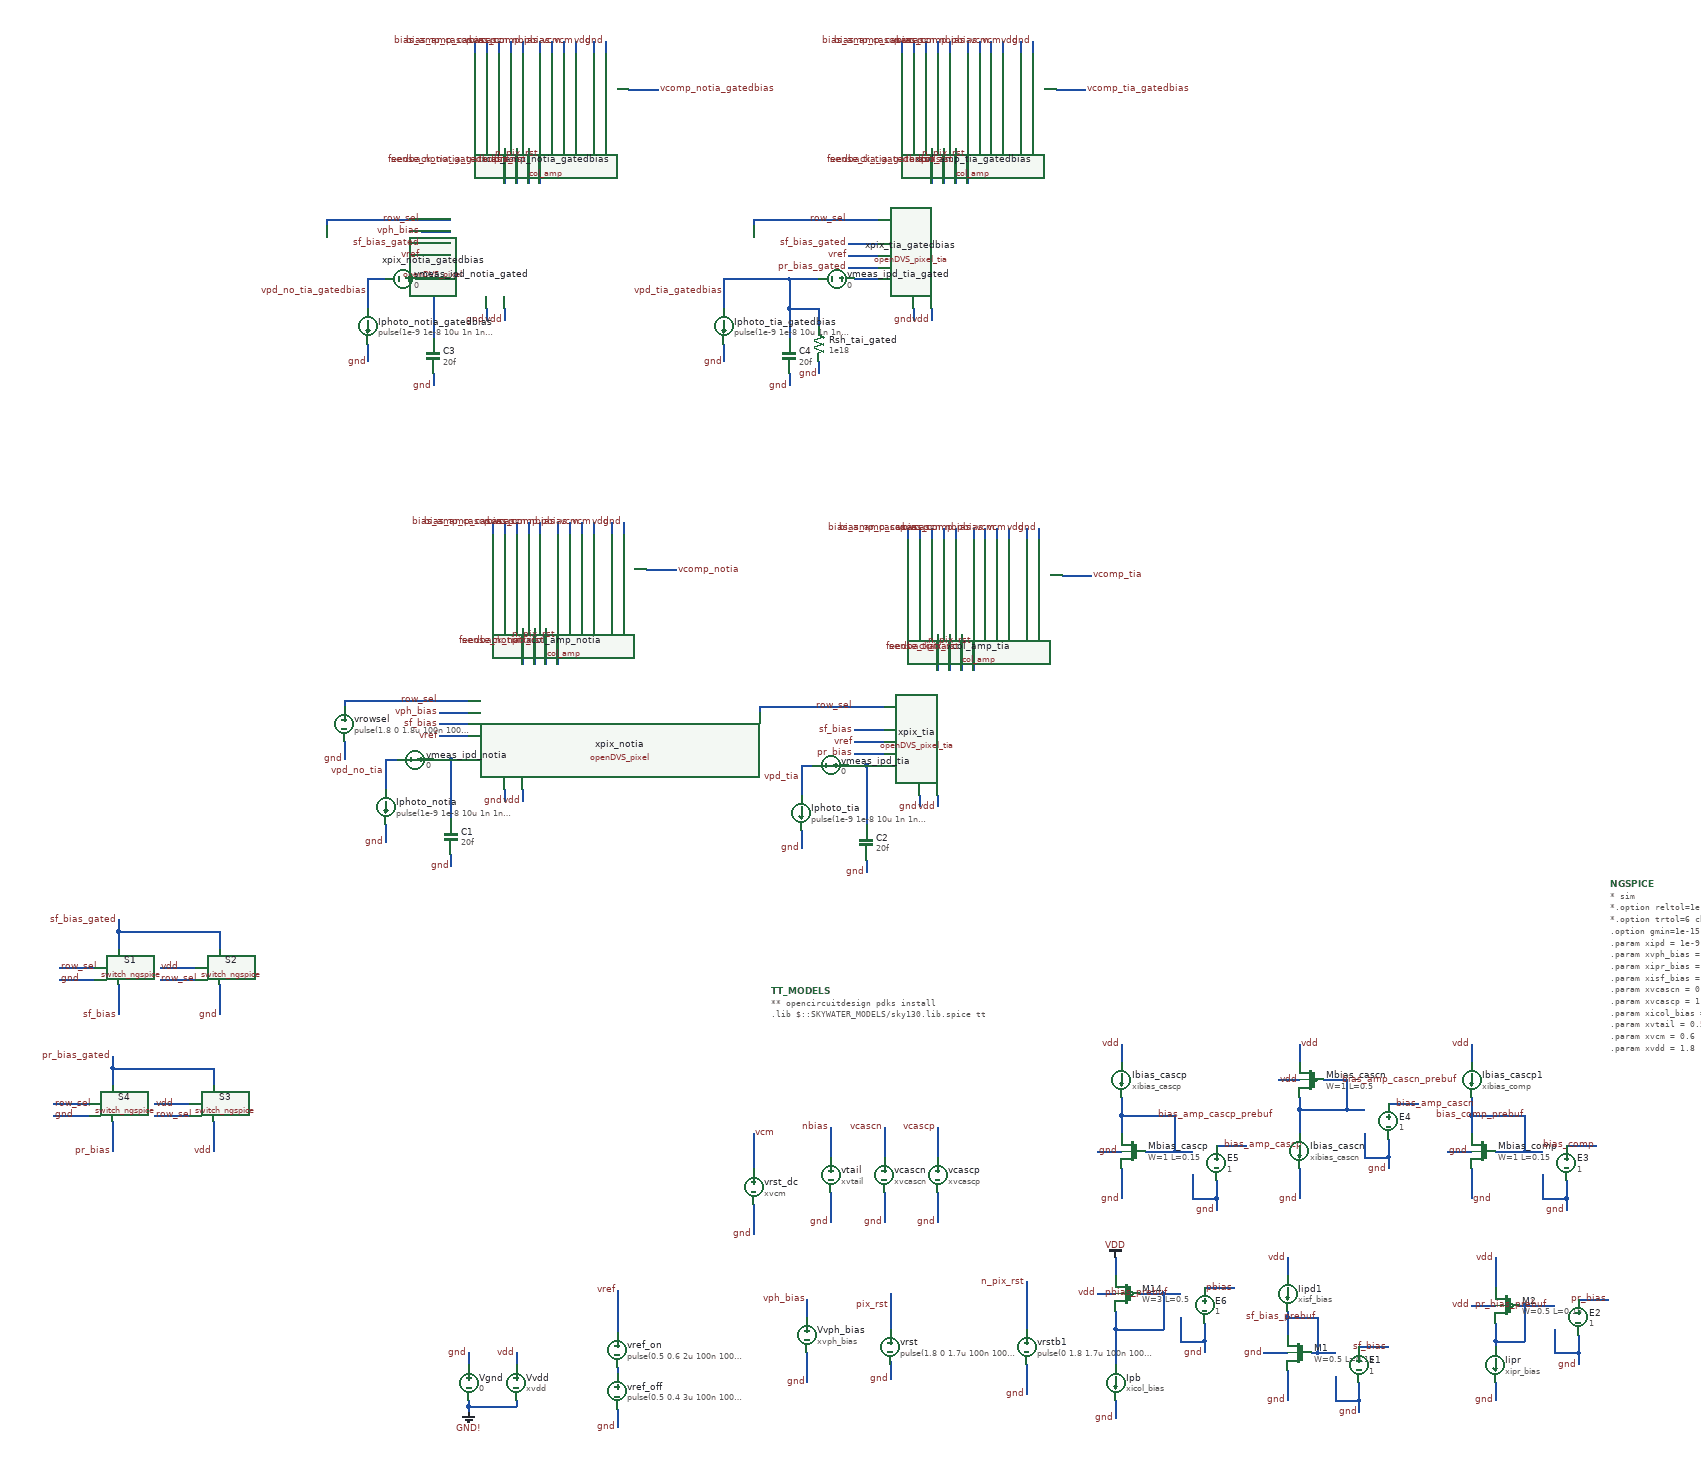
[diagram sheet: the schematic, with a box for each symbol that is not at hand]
v {xschem version=3.4.8RC file_version=1.2}
G {}
K {}
V {}
S {}
E {}
N 1550 -260 1550 -200 {lab=pbias_prebuf}
N 1550 -380 1550 -350 {lab=VDD}
N 1520 -320 1550 -320 {lab=vdd}
N 1630 -320 1630 -260 {lab=pbias_prebuf}
N 1550 -260 1630 -260 {lab=pbias_prebuf}
N 550 -1440 550 -1380 {lab=sense_notia}
N 570 -1440 570 -1380 {lab=feedback_notia}
N 590 -1440 590 -1380 {lab=pix_rst}
N 1840 -280 1840 -250 {lab=sf_bias_prebuf}
N 1890 -280 1890 -220 {lab=sf_bias_prebuf}
N 1840 -190 1840 -140 {lab=gnd}
N 1880 -220 1890 -220 {lab=sf_bias_prebuf}
N 1840 -280 1890 -280 {lab=sf_bias_prebuf}
N 1960 -230 2010 -230 {lab=sf_bias}
N 1840 -380 1840 -350 {lab=vdd}
N 710 -125 710 -95 {lab=gnd}
N 1030 -220 1030 -170 {lab=gnd}
N 1030 -310 1030 -280 {lab=vph_bias}
N 320 -1110 320 -1080 {lab=gnd}
N 320 -1220 320 -1170 {lab=vpd_no_tia}
N 320 -1220 350 -1220 {lab=vpd_no_tia}
N 410 -1280 460 -1280 {lab=sf_bias}
N 410 -1260 460 -1260 {lab=vref}
N 410 -1300 460 -1300 {lab=vph_bias}
N 460 -130 460 -120 {lab=GND!}
N 460 -130 540 -130 {lab=GND!}
N 540 -140 540 -130 {lab=GND!}
N 540 -220 540 -200 {lab=vdd}
N 460 -220 460 -200 {lab=gnd}
N 520 -1170 520 -1150 {lab=gnd}
N 550 -1170 550 -1150 {lab=vdd}
N 720 -1620 720 -1600 {lab=gnd}
N 700 -1620 700 -1600 {lab=vdd}
N 760 -1540 810 -1540 {lab=vcomp_notia}
N 630 -1620 630 -1600 {lab=pbias}
N 610 -1620 610 -1600 {lab=nbias}
N 1070 -490 1070 -440 {lab=gnd}
N 1070 -600 1070 -550 {lab=nbias}
N 1160 -490 1160 -440 {lab=gnd}
N 1160 -600 1160 -550 {lab=vcascn}
N 1250 -490 1250 -440 {lab=gnd}
N 1250 -600 1250 -550 {lab=vcascp}
N 580 -1620 580 -1600 {lab=bias_comp}
N 560 -1620 560 -1600 {lab=vcascn}
N 540 -1620 540 -1600 {lab=vcascp}
N 520 -1620 520 -1600 {lab=bias_amp_cascn}
N 500 -1620 500 -1600 {lab=bias_amp_cascp}
N 1560 -620 1560 -590 {lab=bias_amp_cascp_prebuf}
N 1560 -530 1560 -480 {lab=gnd}
N 1520 -560 1560 -560 {lab=gnd}
N 1600 -560 1650 -560 {lab=bias_amp_cascp_prebuf}
N 1650 -620 1650 -560 {lab=bias_amp_cascp_prebuf}
N 1560 -620 1650 -620 {lab=bias_amp_cascp_prebuf}
N 1560 -650 1560 -620 {lab=bias_amp_cascp_prebuf}
N 1560 -740 1560 -710 {lab=vdd}
N 1860 -630 1860 -590 {lab=bias_amp_cascn_prebuf}
N 1860 -530 1860 -480 {lab=gnd}
N 1860 -740 1860 -710 {lab=vdd}
N 1900 -680 1940 -680 {lab=bias_amp_cascn_prebuf}
N 1940 -680 1940 -630 {lab=bias_amp_cascn_prebuf}
N 1860 -630 1940 -630 {lab=bias_amp_cascn_prebuf}
N 940 -590 940 -530 {lab=vcm}
N 940 -470 940 -420 {lab=gnd}
N 650 -1620 650 -1600 {lab=vcm}
N 2150 -620 2150 -590 {lab=bias_comp_prebuf}
N 2150 -530 2150 -480 {lab=gnd}
N 2110 -560 2150 -560 {lab=gnd}
N 2190 -560 2240 -560 {lab=bias_comp_prebuf}
N 2240 -620 2240 -560 {lab=bias_comp_prebuf}
N 2150 -620 2240 -620 {lab=bias_comp_prebuf}
N 2150 -650 2150 -620 {lab=bias_comp_prebuf}
N 2150 -740 2150 -710 {lab=vdd}
N 1825 -680 1860 -680 {lab=vdd}
N 1800 -220 1840 -220 {lab=gnd}
N 1550 -140 1550 -110 {lab=gnd}
N 710 -195 710 -185 {lab=#net1}
N 710 -325 710 -255 {lab=vref}
N 1590 -320 1630 -320 {lab=pbias_prebuf}
N 1550 -290 1550 -260 {lab=pbias_prebuf}
N 1840 -290 1840 -280 {lab=sf_bias_prebuf}
N 460 -140 460 -130 {lab=GND!}
N 1860 -650 1860 -630 {lab=bias_amp_cascn_prebuf}
N 250 -1320 460 -1320 {lab=row_sel}
N 250 -1320 250 -1310 {lab=row_sel}
N 250 -1250 250 -1220 {lab=gnd}
N 1170 -205 1170 -175 {lab=gnd}
N 1170 -320 1170 -260 {lab=pix_rst}
N 670 -1620 670 -1600 {lab=vcm}
N 1400 -200 1400 -150 {lab=gnd}
N 1400 -340 1400 -260 {lab=n_pix_rst}
N 610 -1440 610 -1380 {lab=n_pix_rst}
N 430 -1220 460 -1220 {lab=#net2}
N 1250 -1430 1250 -1370 {lab=sense_tia}
N 1270 -1430 1270 -1370 {lab=feedback_tia}
N 1290 -1430 1290 -1370 {lab=pix_rst}
N 1020 -1100 1020 -1070 {lab=gnd}
N 1020 -1210 1020 -1160 {lab=vpd_tia}
N 1020 -1210 1050 -1210 {lab=vpd_tia}
N 1110 -1270 1160 -1270 {lab=sf_bias}
N 1110 -1250 1160 -1250 {lab=vref}
N 1110 -1230 1160 -1230 {lab=pr_bias}
N 1220 -1160 1220 -1140 {lab=gnd}
N 1250 -1160 1250 -1140 {lab=vdd}
N 1420 -1610 1420 -1590 {lab=gnd}
N 1400 -1610 1400 -1590 {lab=vdd}
N 1460 -1530 1510 -1530 {lab=vcomp_tia}
N 1330 -1610 1330 -1590 {lab=pbias}
N 1310 -1610 1310 -1590 {lab=nbias}
N 1280 -1610 1280 -1590 {lab=bias_comp}
N 1260 -1610 1260 -1590 {lab=vcascn}
N 1240 -1610 1240 -1590 {lab=vcascp}
N 1220 -1610 1220 -1590 {lab=bias_amp_cascn}
N 1200 -1610 1200 -1590 {lab=bias_amp_cascp}
N 1350 -1610 1350 -1590 {lab=vcm}
N 950 -1310 1160 -1310 {lab=row_sel}
N 950 -1310 950 -1300 {lab=row_sel}
N 1370 -1610 1370 -1590 {lab=vcm}
N 1310 -1430 1310 -1370 {lab=n_pix_rst}
N 1130 -1210 1160 -1210 {lab=#net3}
N 2190 -270 2190 -240 {lab=pr_bias_prebuf}
N 2240 -300 2240 -240 {lab=pr_bias_prebuf}
N 2190 -380 2190 -330 {lab=vdd}
N 2230 -300 2240 -300 {lab=pr_bias_prebuf}
N 2190 -240 2240 -240 {lab=pr_bias_prebuf}
N 2190 -170 2190 -140 {lab=gnd}
N 2150 -300 2190 -300 {lab=vdd}
N 2190 -240 2190 -230 {lab=pr_bias_prebuf}
N 430 -1220 430 -1120 {lab=#net2}
N 430 -1060 430 -1040 {lab=gnd}
N 1130 -1210 1130 -1110 {lab=#net3}
N 1130 -1050 1130 -1030 {lab=gnd}
N 1890 -220 1920 -220 {lab=sf_bias_prebuf}
N 1960 -140 1960 -120 {lab=gnd}
N 1920 -140 1960 -140 {lab=gnd}
N 1920 -180 1920 -140 {lab=gnd}
N 2330 -310 2380 -310 {lab=pr_bias}
N 2330 -220 2330 -200 {lab=gnd}
N 2290 -220 2330 -220 {lab=gnd}
N 2290 -260 2290 -220 {lab=gnd}
N 2240 -300 2290 -300 {lab=pr_bias_prebuf}
N 2310 -570 2360 -570 {lab=bias_comp}
N 2240 -560 2270 -560 {lab=bias_comp_prebuf}
N 2310 -480 2310 -460 {lab=gnd}
N 2270 -480 2310 -480 {lab=gnd}
N 2270 -520 2270 -480 {lab=gnd}
N 2010 -640 2060 -640 {lab=bias_amp_cascn}
N 1940 -630 1970 -630 {lab=bias_amp_cascn_prebuf}
N 2010 -550 2010 -530 {lab=gnd}
N 1970 -550 2010 -550 {lab=gnd}
N 1970 -590 1970 -550 {lab=gnd}
N 1720 -570 1770 -570 {lab=bias_amp_cascp}
N 1650 -560 1680 -560 {lab=bias_amp_cascp_prebuf}
N 1720 -480 1720 -460 {lab=gnd}
N 1680 -480 1720 -480 {lab=gnd}
N 1680 -520 1680 -480 {lab=gnd}
N 1700 -330 1750 -330 {lab=pbias}
N 1630 -320 1660 -320 {lab=pbias_prebuf}
N 1700 -240 1700 -220 {lab=gnd}
N 1660 -240 1700 -240 {lab=gnd}
N 1660 -280 1660 -240 {lab=gnd}
N 520 -2250 520 -2190 {lab=sense_notia_gatedbias}
N 540 -2250 540 -2190 {lab=feedback_notia_gatedbias}
N 560 -2250 560 -2190 {lab=pix_rst}
N 290 -1920 290 -1890 {lab=gnd}
N 290 -2030 290 -1980 {lab=vpd_no_tia_gatedbias}
N 290 -2030 320 -2030 {lab=vpd_no_tia_gatedbias}
N 380 -2090 430 -2090 {lab=sf_bias_gated}
N 380 -2070 430 -2070 {lab=vref}
N 380 -2110 430 -2110 {lab=vph_bias}
N 490 -1980 490 -1960 {lab=gnd}
N 520 -1980 520 -1960 {lab=vdd}
N 690 -2430 690 -2410 {lab=gnd}
N 670 -2430 670 -2410 {lab=vdd}
N 730 -2350 780 -2350 {lab=vcomp_notia_gatedbias}
N 600 -2430 600 -2410 {lab=pbias}
N 580 -2430 580 -2410 {lab=nbias}
N 550 -2430 550 -2410 {lab=bias_comp}
N 530 -2430 530 -2410 {lab=vcascn}
N 510 -2430 510 -2410 {lab=vcascp}
N 490 -2430 490 -2410 {lab=bias_amp_cascn}
N 470 -2430 470 -2410 {lab=bias_amp_cascp}
N 620 -2430 620 -2410 {lab=vcm}
N 220 -2130 430 -2130 {lab=row_sel}
N 220 -2130 220 -2120 {lab=row_sel}
N 640 -2430 640 -2410 {lab=vcm}
N 580 -2250 580 -2190 {lab=n_pix_rst}
N 400 -2030 430 -2030 {lab=#net4}
N 400 -2030 400 -1930 {lab=#net4}
N 400 -1870 400 -1850 {lab=gnd}
N -130 -840 -130 -790 {lab=sf_bias}
N -130 -930 -130 -900 {lab=sf_bias_gated}
N -230 -870 -170 -870 {lab=row_sel}
N -130 -930 40 -930 {lab=sf_bias_gated}
N 40 -930 40 -900 {lab=sf_bias_gated}
N -60 -850 0 -850 {lab=row_sel}
N -60 -870 0 -870 {lab=vdd}
N 40 -840 40 -790 {lab=gnd}
N -230 -850 -170 -850 {lab=gnd}
N -140 -610 -140 -560 {lab=pr_bias}
N -140 -700 -140 -670 {lab=pr_bias_gated}
N -240 -640 -180 -640 {lab=row_sel}
N -140 -700 30 -700 {lab=pr_bias_gated}
N 30 -700 30 -670 {lab=pr_bias_gated}
N -70 -620 -10 -620 {lab=row_sel}
N -70 -640 -10 -640 {lab=vdd}
N 30 -610 30 -560 {lab=vdd}
N -240 -620 -180 -620 {lab=gnd}
N 1240 -2250 1240 -2190 {lab=sense_tia_gatedbias}
N 1260 -2250 1260 -2190 {lab=feedback_tia_gatedbias}
N 1280 -2250 1280 -2190 {lab=pix_rst}
N 890 -1920 890 -1890 {lab=gnd}
N 890 -2030 890 -1980 {lab=vpd_tia_gatedbias}
N 890 -2030 1000 -2030 {lab=vpd_tia_gatedbias}
N 1100 -2090 1150 -2090 {lab=sf_bias_gated}
N 1100 -2070 1150 -2070 {lab=vref}
N 1100 -2050 1150 -2050 {lab=pr_bias_gated}
N 1210 -1980 1210 -1960 {lab=gnd}
N 1240 -1980 1240 -1960 {lab=vdd}
N 1410 -2430 1410 -2410 {lab=gnd}
N 1390 -2430 1390 -2410 {lab=vdd}
N 1450 -2350 1500 -2350 {lab=vcomp_tia_gatedbias}
N 1320 -2430 1320 -2410 {lab=pbias}
N 1300 -2430 1300 -2410 {lab=nbias}
N 1270 -2430 1270 -2410 {lab=bias_comp}
N 1250 -2430 1250 -2410 {lab=vcascn}
N 1230 -2430 1230 -2410 {lab=vcascp}
N 1210 -2430 1210 -2410 {lab=bias_amp_cascn}
N 1190 -2430 1190 -2410 {lab=bias_amp_cascp}
N 1340 -2430 1340 -2410 {lab=vcm}
N 940 -2130 1150 -2130 {lab=row_sel}
N 940 -2130 940 -2120 {lab=row_sel}
N 1360 -2430 1360 -2410 {lab=vcm}
N 1300 -2250 1300 -2190 {lab=n_pix_rst}
N 1000 -2030 1050 -2030 {lab=vpd_tia_gatedbias}
N 1000 -1980 1000 -1930 {lab=vpd_tia_gatedbias}
N 1000 -1870 1000 -1850 {lab=gnd}
N 1050 -1890 1050 -1870 {lab=gnd}
N 1050 -1980 1050 -1950 {lab=vpd_tia_gatedbias}
N 1000 -1980 1050 -1980 {lab=vpd_tia_gatedbias}
N 1110 -2030 1150 -2030 {lab=#net5}
N 400 -1220 430 -1220 {lab=#net2}
N 1100 -1210 1130 -1210 {lab=#net3}
N 1960 -170 1960 -140 {lab=gnd}
N 2330 -250 2330 -220 {lab=gnd}
N 2310 -510 2310 -480 {lab=gnd}
N 2010 -580 2010 -550 {lab=gnd}
N 1720 -510 1720 -480 {lab=gnd}
N 1700 -270 1700 -240 {lab=gnd}
N 370 -2030 400 -2030 {lab=#net4}
N -130 -950 -130 -930 {lab=sf_bias_gated}
N -140 -720 -140 -700 {lab=pr_bias_gated}
N 1000 -2030 1000 -1980 {lab=vpd_tia_gatedbias}
C {devices/code.sym} 970 -830 0 0 {name=TT_MODELS
only_toplevel=true
format="tcleval( @value )"
value="
** opencircuitdesign pdks install
.lib $::SKYWATER_MODELS/sky130.lib.spice tt
"
spice_ignore=false}
C {code_shown.sym} 2385 -1010 0 0 {name=NGSPICE
only_toplevel=true
value="* sim
*.option reltol=1e-3 abstol=1e-12 vntol=1e-5 gmin=1e-10 
*.option trtol=6 chgtol=1e-12
.option gmin=1e-15

.param xipd = 1e-9
.param xvph_bias = 1.5
.param xipr_bias = 10n
.param xisf_bias = 20f
.param xvcascn = 0.2
.param xvcascp = 1.6
.param xicol_bias = 5e-7
.param xvtail = 0.5
.param xvcm = 0.6
.param xvdd = 1.8
.param xibias_cascp = 50n
.param xibias_cascn = 50n
.param xibias_comp = 50n


.control
* plot v(vref) v(sense) v(feedback) v(pix_rst)
save v(vref) v(sense) v(feedback) v(pix_rst)
save v(vcomp) v(xcol_amp.vout_sense)
save all
tran .1n 29u


* save v(vphoto) v(vph_sf) v(vin) v(sense) v(feedback) v(vcomp)
* save v(pix_rst) v(vout) v(pbchk) v(vref) v(row_sel) v(lrst)
*ic v(vin)=0.6
*ic v(vout)=1
* dc vph 0 1.8 10m
*save all
* op
* write 1x1array_tb.raw
.endc
"}
C {devices/launcher.sym} 1040 -910 2 1 {name=h1
descr="Annotate OP" 
tclcommand="set show_hidden_texts 1; xschem annotate_op"
}
C {isource.sym} 1550 -170 0 0 {name=Ipb value=xicol_bias}
C {sky130_fd_pr/pfet_01v8.sym} 1570 -320 0 1 {name=M14
W=3
L=0.5
nf=1
mult=1
ad="expr('int((@nf + 1)/2) * @W / @nf * 0.29')"
pd="expr('2*int((@nf + 1)/2) * (@W / @nf + 0.29)')"
as="expr('int((@nf + 2)/2) * @W / @nf * 0.29')"
ps="expr('2*int((@nf + 2)/2) * (@W / @nf + 0.29)')"
nrd="expr('0.29 / @W ')" nrs="expr('0.29 / @W ')"
sa=0 sb=0 sd=0
model=pfet_01v8
spiceprefix=X
}
C {vdd.sym} 1550 -380 0 0 {name=l36 lab=VDD}
C {col_amp.sym} 610 -1480 0 0 {name=xcol_amp_notia}
C {openDVS_pixel.sym} 610 -1250 0 0 {name=xpix_notia}
C {sky130_fd_pr/nfet_01v8.sym} 1860 -220 0 1 {name=M1
W=0.5
L=0.15
nf=1 
mult=1
ad="expr('int((@nf + 1)/2) * @W / @nf * 0.29')"
pd="expr('2*int((@nf + 1)/2) * (@W / @nf + 0.29)')"
as="expr('int((@nf + 2)/2) * @W / @nf * 0.29')"
ps="expr('2*int((@nf + 2)/2) * (@W / @nf + 0.29)')"
nrd="expr('0.29 / @W ')" nrs="expr('0.29 / @W ')"
sa=0 sb=0 sd=0
model=nfet_01v8
spiceprefix=X
}
C {isource.sym} 1840 -320 0 0 {name=Iipd1 value=xisf_bias}
C {lab_wire.sym} 1840 -140 0 0 {name=p3 sig_type=std_logic lab=gnd}
C {lab_wire.sym} 2010 -230 0 0 {name=p5 sig_type=std_logic lab=sf_bias}
C {lab_wire.sym} 1840 -380 0 0 {name=p6 sig_type=std_logic lab=vdd}
C {lab_wire.sym} 710 -95 0 0 {name=Vvref1 sig_type=std_logic lab=gnd
value=vref}
C {vsource.sym} 1030 -250 0 0 {name=Vvph_bias value=xvph_bias savecurrent=false}
C {lab_wire.sym} 1030 -170 0 0 {name=Vvref4 sig_type=std_logic lab=gnd
value=vref}
C {lab_wire.sym} 1030 -310 0 0 {name=Vvref5 sig_type=std_logic lab=vph_bias
value=vph_bias}
C {lab_wire.sym} 320 -1080 0 0 {name=p2 sig_type=std_logic lab=gnd}
C {lab_wire.sym} 410 -1280 0 0 {name=p7 sig_type=std_logic lab=sf_bias}
C {lab_wire.sym} 410 -1260 0 0 {name=p10 sig_type=std_logic lab=vref}
C {lab_wire.sym} 410 -1300 0 0 {name=p15 sig_type=std_logic lab=vph_bias}
C {lab_wire.sym} 320 -1200 0 0 {name=p8 sig_type=std_logic lab=vpd_no_tia}
C {vsource.sym} 460 -170 0 0 {name=Vgnd value=0 savecurrent=false}
C {gnd.sym} 460 -120 0 0 {name=l1 lab=GND!}
C {vsource.sym} 540 -170 0 0 {name=Vvdd value=xvdd savecurrent=false}
C {lab_wire.sym} 460 -220 0 0 {name=p1 sig_type=std_logic lab=gnd}
C {lab_wire.sym} 540 -220 0 0 {name=p4 sig_type=std_logic lab=vdd}
C {lab_wire.sym} 520 -1150 3 0 {name=p9 sig_type=std_logic lab=gnd}
C {lab_wire.sym} 550 -1150 3 0 {name=p11 sig_type=std_logic lab=vdd}
C {lab_wire.sym} 720 -1620 3 1 {name=p12 sig_type=std_logic lab=gnd}
C {lab_wire.sym} 700 -1620 3 1 {name=p14 sig_type=std_logic lab=vdd}
C {lab_wire.sym} 550 -1420 3 0 {name=p16 sig_type=std_logic lab=sense_notia}
C {lab_wire.sym} 590 -1420 3 0 {name=p17 sig_type=std_logic lab=pix_rst}
C {lab_wire.sym} 570 -1420 3 0 {name=p18 sig_type=std_logic lab=feedback_notia}
C {lab_wire.sym} 1750 -330 0 0 {name=p19 sig_type=std_logic lab=pbias}
C {lab_wire.sym} 810 -1540 2 0 {name=p20 sig_type=std_logic lab=vcomp_notia}
C {lab_wire.sym} 630 -1620 3 1 {name=p21 sig_type=std_logic lab=pbias}
C {lab_wire.sym} 610 -1620 3 1 {name=p22 sig_type=std_logic lab=nbias
}
C {vsource.sym} 1070 -520 0 0 {name=vtail value=xvtail savecurrent=false}
C {lab_wire.sym} 1070 -440 0 0 {name=Vvref3 sig_type=std_logic lab=gnd
value=vref}
C {lab_wire.sym} 1070 -600 0 0 {name=p23 sig_type=std_logic lab=nbias}
C {vsource.sym} 1160 -520 0 0 {name=vcascn value=xvcascn savecurrent=false}
C {lab_wire.sym} 1160 -440 0 0 {name=Vvref6 sig_type=std_logic lab=gnd
value=vref}
C {lab_wire.sym} 1160 -600 0 0 {name=p24 sig_type=std_logic lab=vcascn}
C {vsource.sym} 1250 -520 0 0 {name=vcascp value=xvcascp savecurrent=false}
C {lab_wire.sym} 1250 -440 0 0 {name=vcascp1 sig_type=std_logic lab=gnd
value=xcascp}
C {lab_wire.sym} 1250 -600 0 0 {name=vcascp2 sig_type=std_logic lab=vcascp
value=xcascp}
C {lab_wire.sym} 560 -1620 3 1 {name=p25 sig_type=std_logic lab=vcascn
}
C {lab_wire.sym} 540 -1620 3 1 {name=p26 sig_type=std_logic lab=vcascp}
C {sky130_fd_pr/nfet_01v8.sym} 1580 -560 0 1 {name=Mbias_cascp
W=1
L=0.15
nf=1 
mult=1
ad="expr('int((@nf + 1)/2) * @W / @nf * 0.29')"
pd="expr('2*int((@nf + 1)/2) * (@W / @nf + 0.29)')"
as="expr('int((@nf + 2)/2) * @W / @nf * 0.29')"
ps="expr('2*int((@nf + 2)/2) * (@W / @nf + 0.29)')"
nrd="expr('0.29 / @W ')" nrs="expr('0.29 / @W ')"
sa=0 sb=0 sd=0
model=nfet_01v8
spiceprefix=X
}
C {lab_wire.sym} 1520 -560 0 1 {name=p28 sig_type=std_logic lab=gnd}
C {lab_wire.sym} 1560 -480 0 0 {name=vcascp3 sig_type=std_logic lab=gnd
value=xcascp}
C {isource.sym} 1560 -680 0 0 {name=Ibias_cascp value=xibias_cascp}
C {lab_wire.sym} 1560 -740 0 0 {name=p27 sig_type=std_logic lab=vdd}
C {lab_wire.sym} 1730 -570 0 1 {name=vcascp4 sig_type=std_logic lab=bias_amp_cascp}
C {lab_wire.sym} 500 -1620 3 1 {name=vcascp5 sig_type=std_logic lab=bias_amp_cascp}
C {lab_wire.sym} 520 -1620 3 1 {name=vcascp6 sig_type=std_logic lab=bias_amp_cascn}
C {sky130_fd_pr/pfet_01v8.sym} 1880 -680 0 1 {name=Mbias_cascn
W=1
L=0.5
nf=1
mult=1
ad="expr('int((@nf + 1)/2) * @W / @nf * 0.29')"
pd="expr('2*int((@nf + 1)/2) * (@W / @nf + 0.29)')"
as="expr('int((@nf + 2)/2) * @W / @nf * 0.29')"
ps="expr('2*int((@nf + 2)/2) * (@W / @nf + 0.29)')"
nrd="expr('0.29 / @W ')" nrs="expr('0.29 / @W ')"
sa=0 sb=0 sd=0
model=pfet_01v8
spiceprefix=X
}
C {isource.sym} 1860 -560 0 0 {name=Ibias_cascn value=xibias_cascn}
C {lab_wire.sym} 1860 -480 0 0 {name=vcascp7 sig_type=std_logic lab=gnd
value=xcascp}
C {lab_wire.sym} 1860 -740 0 1 {name=p29 sig_type=std_logic lab=vdd}
C {lab_wire.sym} 2020 -640 2 0 {name=vcascp8 sig_type=std_logic lab=bias_amp_cascn}
C {vsource.sym} 940 -500 0 0 {name=vrst_dc value=xvcm savecurrent=false}
C {lab_wire.sym} 940 -420 0 0 {name=vcascp10 sig_type=std_logic lab=gnd
value=xcascp}
C {lab_wire.sym} 650 -1620 3 1 {name=p31 sig_type=std_logic lab=vcm}
C {lab_wire.sym} 940 -590 0 1 {name=p32 sig_type=std_logic lab=vcm}
C {lab_wire.sym} 2110 -560 0 1 {name=p33 sig_type=std_logic lab=gnd}
C {lab_wire.sym} 2150 -480 0 1 {name=vcascp11 sig_type=std_logic lab=gnd
value=xcascp}
C {isource.sym} 2150 -680 0 0 {name=Ibias_cascp1 value=xibias_comp}
C {lab_wire.sym} 2150 -740 0 0 {name=p34 sig_type=std_logic lab=vdd}
C {sky130_fd_pr/nfet_01v8.sym} 2170 -560 0 1 {name=Mbias_comp
W=1
L=0.15
nf=1 
mult=1
ad="expr('int((@nf + 1)/2) * @W / @nf * 0.29')"
pd="expr('2*int((@nf + 1)/2) * (@W / @nf + 0.29)')"
as="expr('int((@nf + 2)/2) * @W / @nf * 0.29')"
ps="expr('2*int((@nf + 2)/2) * (@W / @nf + 0.29)')"
nrd="expr('0.29 / @W ')" nrs="expr('0.29 / @W ')"
sa=0 sb=0 sd=0
model=nfet_01v8
spiceprefix=X
}
C {lab_wire.sym} 580 -1620 3 1 {name=vcascp13 sig_type=std_logic lab=bias_comp}
C {lab_wire.sym} 1520 -320 0 0 {name=p35 sig_type=std_logic lab=vdd}
C {lab_wire.sym} 1825 -680 0 1 {name=p36 sig_type=std_logic lab=vdd}
C {lab_wire.sym} 1800 -220 0 0 {name=p37 sig_type=std_logic lab=gnd}
C {lab_wire.sym} 1550 -110 0 0 {name=p38 sig_type=std_logic lab=gnd}
C {vsource.sym} 710 -225 0 0 {name=vref_on value="pulse(0.5 0.6 2u 100n 100n 0.7u 3u)" savecurrent=false}
C {vsource.sym} 710 -155 0 0 {name=vref_off value="pulse(0.5 0.4 3u 100n 100n 0.7u 3u)" savecurrent=false}
C {lab_wire.sym} 710 -325 3 0 {name=p39 sig_type=std_logic lab=vref}
C {noconn.sym} 810 -1540 2 0 {name=l2}
C {isource.sym} 320 -1140 0 0 {name=Iphoto_notia value="pulse(1e-9 1e-8 10u 1n 1n 12u 24u)"}
C {vsource.sym} 250 -1280 0 0 {name=vrowsel value="pulse(1.8 0 1.8u 100n 100n 3u 6u)" savecurrent=false}
C {lab_wire.sym} 250 -1220 0 0 {name=p13 sig_type=std_logic lab=gnd}
C {lab_wire.sym} 410 -1320 0 0 {name=p41 sig_type=std_logic lab=row_sel}
C {vsource.sym} 1170 -230 0 0 {name=vrst value="pulse(1.8 0 1.7u 100n 100n 2.3u 3u)" savecurrent=false}
C {lab_wire.sym} 1170 -175 0 0 {name=Vvref2 sig_type=std_logic lab=gnd
value=vref}
C {lab_wire.sym} 1170 -300 3 0 {name=p42 sig_type=std_logic lab=pix_rst}
C {lab_wire.sym} 670 -1620 3 1 {name=p43 sig_type=std_logic lab=vcm}
C {vsource.sym} 1400 -230 0 0 {name=vrstb1 value="pulse(0 1.8 1.7u 100n 100n 2.3u 3u)" savecurrent=false}
C {lab_wire.sym} 1400 -150 0 0 {name=vrstb2 sig_type=std_logic lab=gnd
value=xcascp}
C {lab_wire.sym} 1400 -340 3 0 {name=p44 sig_type=std_logic lab=n_pix_rst}
C {lab_wire.sym} 610 -1430 3 0 {name=p45 sig_type=std_logic lab=n_pix_rst}
C {col_amp.sym} 1310 -1470 0 0 {name=xcol_amp_tia}
C {openDVS_pixel_tia.sym} 1310 -1240 0 0 {name=xpix_tia}
C {lab_wire.sym} 1020 -1070 0 0 {name=p30 sig_type=std_logic lab=gnd}
C {lab_wire.sym} 1110 -1270 0 0 {name=p40 sig_type=std_logic lab=sf_bias}
C {lab_wire.sym} 1110 -1250 0 0 {name=p46 sig_type=std_logic lab=vref}
C {lab_wire.sym} 1110 -1230 0 0 {name=p47 sig_type=std_logic lab=pr_bias}
C {lab_wire.sym} 1020 -1190 0 0 {name=p48 sig_type=std_logic lab=vpd_tia}
C {lab_wire.sym} 1220 -1140 3 0 {name=p49 sig_type=std_logic lab=gnd}
C {lab_wire.sym} 1250 -1140 3 0 {name=p50 sig_type=std_logic lab=vdd}
C {lab_wire.sym} 1420 -1610 3 1 {name=p51 sig_type=std_logic lab=gnd}
C {lab_wire.sym} 1400 -1610 3 1 {name=p52 sig_type=std_logic lab=vdd}
C {lab_wire.sym} 1250 -1410 3 0 {name=p53 sig_type=std_logic lab=sense_tia}
C {lab_wire.sym} 1290 -1410 3 0 {name=p54 sig_type=std_logic lab=pix_rst}
C {lab_wire.sym} 1270 -1410 3 0 {name=p55 sig_type=std_logic lab=feedback_tia}
C {lab_wire.sym} 1510 -1530 2 0 {name=p56 sig_type=std_logic lab=vcomp_tia}
C {lab_wire.sym} 1330 -1610 3 1 {name=p57 sig_type=std_logic lab=pbias}
C {lab_wire.sym} 1310 -1610 3 1 {name=p58 sig_type=std_logic lab=nbias
}
C {lab_wire.sym} 1260 -1610 3 1 {name=p59 sig_type=std_logic lab=vcascn
}
C {lab_wire.sym} 1240 -1610 3 1 {name=p60 sig_type=std_logic lab=vcascp}
C {lab_wire.sym} 1200 -1610 3 1 {name=vcascp9 sig_type=std_logic lab=bias_amp_cascp}
C {lab_wire.sym} 1220 -1610 3 1 {name=vcascp14 sig_type=std_logic lab=bias_amp_cascn}
C {lab_wire.sym} 1350 -1610 3 1 {name=p61 sig_type=std_logic lab=vcm}
C {lab_wire.sym} 1280 -1610 3 1 {name=vcascp15 sig_type=std_logic lab=bias_comp}
C {noconn.sym} 1510 -1530 2 0 {name=l3}
C {isource.sym} 1020 -1130 0 0 {name=Iphoto_tia value="pulse(1e-9 1e-8 10u 1n 1n 12u 24u)"}
C {lab_wire.sym} 1110 -1310 0 0 {name=p63 sig_type=std_logic lab=row_sel}
C {lab_wire.sym} 1370 -1610 3 1 {name=p64 sig_type=std_logic lab=vcm}
C {lab_wire.sym} 1310 -1420 3 0 {name=p65 sig_type=std_logic lab=n_pix_rst}
C {sky130_fd_pr/pfet_01v8.sym} 2210 -300 0 1 {name=M2
W=0.5
L=0.15
nf=1 
mult=1
ad="expr('int((@nf + 1)/2) * @W / @nf * 0.29')"
pd="expr('2*int((@nf + 1)/2) * (@W / @nf + 0.29)')"
as="expr('int((@nf + 2)/2) * @W / @nf * 0.29')"
ps="expr('2*int((@nf + 2)/2) * (@W / @nf + 0.29)')"
nrd="expr('0.29 / @W ')" nrs="expr('0.29 / @W ')"
sa=0 sb=0 sd=0
model=nfet_01v8
spiceprefix=X
}
C {isource.sym} 2190 -200 0 0 {name=Iipr value=xipr_bias}
C {lab_wire.sym} 2190 -380 2 1 {name=p66 sig_type=std_logic lab=vdd}
C {lab_wire.sym} 2190 -140 2 1 {name=p68 sig_type=std_logic lab=gnd}
C {lab_wire.sym} 2150 -300 2 1 {name=p69 sig_type=std_logic lab=vdd}
C {capa.sym} 430 -1090 0 0 {name=C1
m=1
value=20f
footprint=1206
device="ceramic capacitor"}
C {lab_wire.sym} 430 -1040 3 0 {name=p70 sig_type=std_logic lab=gnd}
C {capa.sym} 1130 -1080 0 0 {name=C2
m=1
value=20f
footprint=1206
device="ceramic capacitor"}
C {lab_wire.sym} 1130 -1030 3 0 {name=p71 sig_type=std_logic lab=gnd}
C {vcvs.sym} 1960 -200 0 0 {name=E1 value=1}
C {lab_wire.sym} 1960 -120 0 0 {name=p62 sig_type=std_logic lab=gnd}
C {lab_wire.sym} 2380 -310 0 0 {name=p72 sig_type=std_logic lab=pr_bias}
C {vcvs.sym} 2330 -280 0 0 {name=E2 value=1}
C {lab_wire.sym} 2330 -200 0 0 {name=p73 sig_type=std_logic lab=gnd}
C {lab_wire.sym} 2360 -570 0 0 {name=p67 sig_type=std_logic lab=bias_comp}
C {vcvs.sym} 2310 -540 0 0 {name=E3 value=1
lab=bias_comp}
C {lab_wire.sym} 2310 -460 0 0 {name=p74 sig_type=std_logic lab=gnd}
C {vcvs.sym} 2010 -610 0 0 {name=E4 value=1
lab=bias_comp}
C {lab_wire.sym} 2010 -530 0 0 {name=p76 sig_type=std_logic lab=gnd}
C {vcvs.sym} 1720 -540 0 0 {name=E5 value=1
lab=bias_comp}
C {lab_wire.sym} 1720 -460 0 0 {name=p75 sig_type=std_logic lab=gnd}
C {vcvs.sym} 1700 -300 0 0 {name=E6 value=1
lab=bias_comp}
C {lab_wire.sym} 1700 -220 0 0 {name=p77 sig_type=std_logic lab=gnd}
C {lab_wire.sym} 1620 -620 0 1 {name=vcascp12 sig_type=std_logic lab=bias_amp_cascp_prebuf}
C {lab_wire.sym} 1930 -680 2 0 {name=vcascp16 sig_type=std_logic lab=bias_amp_cascn_prebuf}
C {lab_wire.sym} 2240 -620 0 0 {name=p78 sig_type=std_logic lab=bias_comp_prebuf}
C {lab_wire.sym} 1640 -320 0 0 {name=p79 sig_type=std_logic lab=pbias_prebuf}
C {lab_wire.sym} 1890 -280 0 0 {name=p80 sig_type=std_logic lab=sf_bias_prebuf}
C {lab_wire.sym} 2280 -300 0 0 {name=p81 sig_type=std_logic lab=pr_bias_prebuf}
C {col_amp.sym} 580 -2290 0 0 {name=xcol_amp_notia_gatedbias}
C {openDVS_pixel.sym} 580 -2060 0 0 {name=xpix_notia_gatedbias}
C {lab_wire.sym} 290 -1890 0 0 {name=p82 sig_type=std_logic lab=gnd}
C {lab_wire.sym} 380 -2090 0 0 {name=p83 sig_type=std_logic lab=sf_bias_gated}
C {lab_wire.sym} 380 -2070 0 0 {name=p84 sig_type=std_logic lab=vref}
C {lab_wire.sym} 380 -2110 0 0 {name=p85 sig_type=std_logic lab=vph_bias}
C {lab_wire.sym} 290 -2010 0 0 {name=p86 sig_type=std_logic lab=vpd_no_tia_gatedbias}
C {lab_wire.sym} 490 -1960 3 0 {name=p87 sig_type=std_logic lab=gnd}
C {lab_wire.sym} 520 -1960 3 0 {name=p88 sig_type=std_logic lab=vdd}
C {lab_wire.sym} 690 -2430 3 1 {name=p89 sig_type=std_logic lab=gnd}
C {lab_wire.sym} 670 -2430 3 1 {name=p90 sig_type=std_logic lab=vdd}
C {lab_wire.sym} 520 -2230 3 0 {name=p91 sig_type=std_logic lab=sense_notia_gatedbias}
C {lab_wire.sym} 560 -2230 3 0 {name=p92 sig_type=std_logic lab=pix_rst}
C {lab_wire.sym} 540 -2230 3 0 {name=p93 sig_type=std_logic lab=feedback_notia_gatedbias}
C {lab_wire.sym} 780 -2350 2 0 {name=p94 sig_type=std_logic lab=vcomp_notia_gatedbias}
C {lab_wire.sym} 600 -2430 3 1 {name=p95 sig_type=std_logic lab=pbias}
C {lab_wire.sym} 580 -2430 3 1 {name=p96 sig_type=std_logic lab=nbias
}
C {lab_wire.sym} 530 -2430 3 1 {name=p97 sig_type=std_logic lab=vcascn
}
C {lab_wire.sym} 510 -2430 3 1 {name=p98 sig_type=std_logic lab=vcascp}
C {lab_wire.sym} 470 -2430 3 1 {name=vcascp17 sig_type=std_logic lab=bias_amp_cascp}
C {lab_wire.sym} 490 -2430 3 1 {name=vcascp18 sig_type=std_logic lab=bias_amp_cascn}
C {lab_wire.sym} 620 -2430 3 1 {name=p99 sig_type=std_logic lab=vcm}
C {lab_wire.sym} 550 -2430 3 1 {name=vcascp19 sig_type=std_logic lab=bias_comp}
C {noconn.sym} 780 -2350 2 0 {name=l4}
C {isource.sym} 290 -1950 0 0 {name=Iphoto_notia_gatedbias value="pulse(1e-9 1e-8 10u 1n 1n 12u 24u)"}
C {lab_wire.sym} 380 -2130 0 0 {name=p101 sig_type=std_logic lab=row_sel}
C {lab_wire.sym} 640 -2430 3 1 {name=p102 sig_type=std_logic lab=vcm}
C {lab_wire.sym} 580 -2240 3 0 {name=p103 sig_type=std_logic lab=n_pix_rst}
C {capa.sym} 400 -1900 0 0 {name=C3
m=1
value=20f
footprint=1206
device="ceramic capacitor"}
C {lab_wire.sym} 400 -1850 3 0 {name=p104 sig_type=std_logic lab=gnd}
C {lab_wire.sym} -130 -790 1 0 {name=p106 sig_type=std_logic lab=sf_bias}
C {lab_wire.sym} -130 -950 1 1 {name=p107 sig_type=std_logic lab=sf_bias_gated}
C {lab_wire.sym} -230 -870 0 1 {name=p108 sig_type=std_logic lab=row_sel}
C {lab_wire.sym} -60 -850 0 1 {name=p110 sig_type=std_logic lab=row_sel}
C {lab_wire.sym} -60 -870 0 1 {name=p111 sig_type=std_logic lab=vdd}
C {lab_wire.sym} 40 -790 0 0 {name=p112 sig_type=std_logic lab=gnd}
C {lab_wire.sym} -230 -850 0 1 {name=p100 sig_type=std_logic lab=gnd}
C {lab_wire.sym} -140 -560 1 0 {name=p105 sig_type=std_logic lab=pr_bias}
C {lab_wire.sym} -140 -720 1 1 {name=p109 sig_type=std_logic lab=pr_bias_gated}
C {lab_wire.sym} -240 -640 0 1 {name=p113 sig_type=std_logic lab=row_sel}
C {lab_wire.sym} -70 -620 0 1 {name=p114 sig_type=std_logic lab=row_sel}
C {lab_wire.sym} -70 -640 0 1 {name=p115 sig_type=std_logic lab=vdd}
C {lab_wire.sym} 30 -560 0 0 {name=p116 sig_type=std_logic lab=vdd}
C {lab_wire.sym} -240 -620 0 1 {name=p117 sig_type=std_logic lab=gnd}
C {col_amp.sym} 1300 -2290 0 0 {name=xcol_amp_tia_gatedbias}
C {openDVS_pixel_tia.sym} 1300 -2060 0 0 {name=xpix_tia_gatedbias}
C {lab_wire.sym} 890 -1890 0 0 {name=p118 sig_type=std_logic lab=gnd}
C {lab_wire.sym} 1100 -2090 0 0 {name=p119 sig_type=std_logic lab=sf_bias_gated}
C {lab_wire.sym} 1100 -2070 0 0 {name=p120 sig_type=std_logic lab=vref}
C {lab_wire.sym} 1100 -2050 0 0 {name=p121 sig_type=std_logic lab=pr_bias_gated}
C {lab_wire.sym} 890 -2010 0 0 {name=p122 sig_type=std_logic lab=vpd_tia_gatedbias}
C {lab_wire.sym} 1210 -1960 3 0 {name=p123 sig_type=std_logic lab=gnd}
C {lab_wire.sym} 1240 -1960 3 0 {name=p124 sig_type=std_logic lab=vdd}
C {lab_wire.sym} 1410 -2430 3 1 {name=p125 sig_type=std_logic lab=gnd}
C {lab_wire.sym} 1390 -2430 3 1 {name=p126 sig_type=std_logic lab=vdd}
C {lab_wire.sym} 1240 -2230 3 0 {name=p127 sig_type=std_logic lab=sense_tia_gatedbias}
C {lab_wire.sym} 1280 -2230 3 0 {name=p128 sig_type=std_logic lab=pix_rst}
C {lab_wire.sym} 1260 -2230 3 0 {name=p129 sig_type=std_logic lab=feedback_tia_gatedbias}
C {lab_wire.sym} 1500 -2350 2 0 {name=p130 sig_type=std_logic lab=vcomp_tia_gatedbias}
C {lab_wire.sym} 1320 -2430 3 1 {name=p131 sig_type=std_logic lab=pbias}
C {lab_wire.sym} 1300 -2430 3 1 {name=p132 sig_type=std_logic lab=nbias
}
C {lab_wire.sym} 1250 -2430 3 1 {name=p133 sig_type=std_logic lab=vcascn
}
C {lab_wire.sym} 1230 -2430 3 1 {name=p134 sig_type=std_logic lab=vcascp}
C {lab_wire.sym} 1190 -2430 3 1 {name=vcascp20 sig_type=std_logic lab=bias_amp_cascp}
C {lab_wire.sym} 1210 -2430 3 1 {name=vcascp21 sig_type=std_logic lab=bias_amp_cascn}
C {lab_wire.sym} 1340 -2430 3 1 {name=p135 sig_type=std_logic lab=vcm}
C {lab_wire.sym} 1270 -2430 3 1 {name=vcascp22 sig_type=std_logic lab=bias_comp}
C {noconn.sym} 1500 -2350 2 0 {name=l5}
C {isource.sym} 890 -1950 0 0 {name=Iphoto_tia_gatedbias value="pulse(1e-9 1e-8 10u 1n 1n 12u 24u)"}
C {lab_wire.sym} 1100 -2130 0 0 {name=p136 sig_type=std_logic lab=row_sel}
C {lab_wire.sym} 1360 -2430 3 1 {name=p137 sig_type=std_logic lab=vcm}
C {lab_wire.sym} 1300 -2240 3 0 {name=p138 sig_type=std_logic lab=n_pix_rst}
C {capa.sym} 1000 -1900 0 0 {name=C4
m=1
value=20f
footprint=1206
device="ceramic capacitor"}
C {lab_wire.sym} 1000 -1850 3 0 {name=p139 sig_type=std_logic lab=gnd}
C {switch_ngspice.sym} -130 -870 0 0 {name=S1 model=SW1
device_model=".MODEL SW1 SW 
+ VT=0.9 VH=0.01
+ RON=0.01 ROFF=10G "}
C {switch_ngspice.sym} 40 -870 0 0 {name=S2 model=SW1
device_model=".MODEL SW1 SW 
+ VT=0.9 VH=0.01
+ RON=0.01 ROFF=10G "}
C {switch_ngspice.sym} 30 -640 0 0 {name=S3 model=SW1
device_model=".MODEL SW1 SW 
+ VT=0.9 VH=0.01
+ RON=0.01 ROFF=10G "}
C {switch_ngspice.sym} -140 -640 0 0 {name=S4 model=SW1
device_model=".MODEL SW1 SW 
+ VT=0.9 VH=0.01
+ RON=0.01 ROFF=10G "}
C {res.sym} 1050 -1920 0 0 {name=Rsh_tai_gated
value=1e18
footprint=1206
device=resistor
m=1}
C {lab_wire.sym} 1050 -1870 3 0 {name=p140 sig_type=std_logic lab=gnd}
C {vsource.sym} 1080 -2030 1 0 {name=vmeas_ipd_tia_gated value=0 savecurrent=false}
C {vsource.sym} 1070 -1210 1 0 {name=vmeas_ipd_tia value=0 savecurrent=false}
C {vsource.sym} 370 -1220 1 0 {name=vmeas_ipd_notia value=0 savecurrent=false}
C {vsource.sym} 350 -2030 1 0 {name=vmeas_ipd_notia_gated value=0 savecurrent=false}
